# Generated by FakeRAM 2.0
VERSION 5.7 ;
BUSBITCHARS "[]" ;
PROPERTYDEFINITIONS
  MACRO width INTEGER ;
  MACRO depth INTEGER ;
  MACRO banks INTEGER ;
END PROPERTYDEFINITIONS
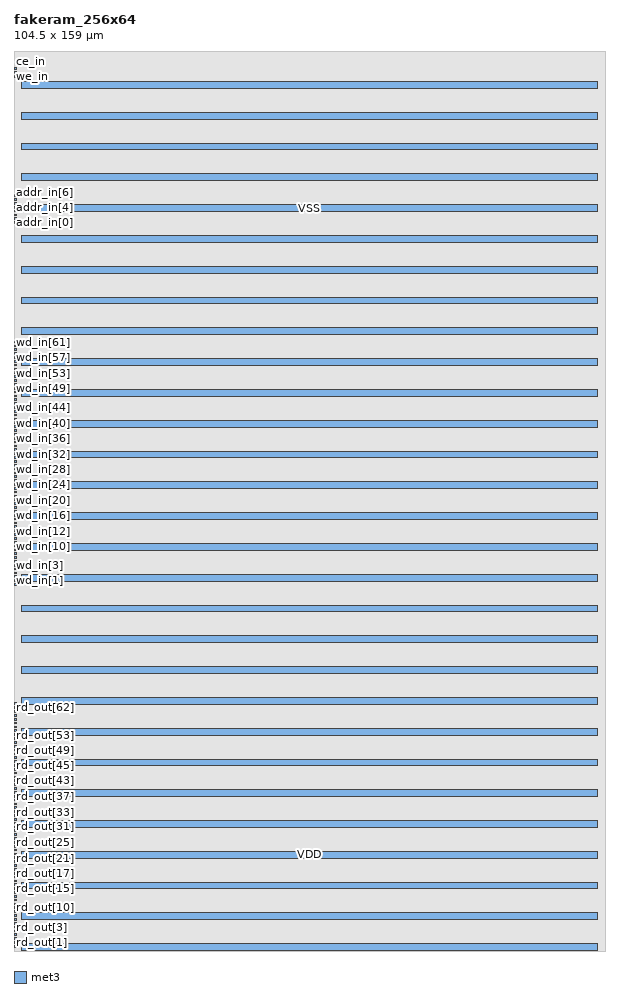
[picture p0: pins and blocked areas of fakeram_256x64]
MACRO fakeram_256x64
  PROPERTY width 64 ;
  PROPERTY depth 256 ;
  PROPERTY banks 1 ;
  FOREIGN fakeram_256x64 0 0 ;
  SYMMETRY X Y R90 ;
  SIZE 104.5000 BY 159.0000 ;
  CLASS BLOCK ;
  PIN rd_out[0]
    DIRECTION OUTPUT ;
    USE SIGNAL ;
    PORT
      LAYER met3 ;
      RECT 0.00000 0.68000 0.45000 0.98000 ;
    END
  END rd_out[0]
  PIN rd_out[1]
    DIRECTION OUTPUT ;
    USE SIGNAL ;
    PORT
      LAYER met3 ;
      RECT 0.00000 1.36000 0.45000 1.66000 ;
    END
  END rd_out[1]
  PIN rd_out[2]
    DIRECTION OUTPUT ;
    USE SIGNAL ;
    PORT
      LAYER met3 ;
      RECT 0.00000 2.04000 0.45000 2.34000 ;
    END
  END rd_out[2]
  PIN rd_out[3]
    DIRECTION OUTPUT ;
    USE SIGNAL ;
    PORT
      LAYER met3 ;
      RECT 0.00000 2.72000 0.45000 3.02000 ;
    END
  END rd_out[3]
  PIN rd_out[4]
    DIRECTION OUTPUT ;
    USE SIGNAL ;
    PORT
      LAYER met3 ;
      RECT 0.00000 3.40000 0.45000 3.70000 ;
    END
  END rd_out[4]
  PIN rd_out[5]
    DIRECTION OUTPUT ;
    USE SIGNAL ;
    PORT
      LAYER met3 ;
      RECT 0.00000 4.08000 0.45000 4.38000 ;
    END
  END rd_out[5]
  PIN rd_out[6]
    DIRECTION OUTPUT ;
    USE SIGNAL ;
    PORT
      LAYER met3 ;
      RECT 0.00000 4.76000 0.45000 5.06000 ;
    END
  END rd_out[6]
  PIN rd_out[7]
    DIRECTION OUTPUT ;
    USE SIGNAL ;
    PORT
      LAYER met3 ;
      RECT 0.00000 5.44000 0.45000 5.74000 ;
    END
  END rd_out[7]
  PIN rd_out[8]
    DIRECTION OUTPUT ;
    USE SIGNAL ;
    PORT
      LAYER met3 ;
      RECT 0.00000 6.12000 0.45000 6.42000 ;
    END
  END rd_out[8]
  PIN rd_out[9]
    DIRECTION OUTPUT ;
    USE SIGNAL ;
    PORT
      LAYER met3 ;
      RECT 0.00000 6.80000 0.45000 7.10000 ;
    END
  END rd_out[9]
  PIN rd_out[10]
    DIRECTION OUTPUT ;
    USE SIGNAL ;
    PORT
      LAYER met3 ;
      RECT 0.00000 7.48000 0.45000 7.78000 ;
    END
  END rd_out[10]
  PIN rd_out[11]
    DIRECTION OUTPUT ;
    USE SIGNAL ;
    PORT
      LAYER met3 ;
      RECT 0.00000 8.16000 0.45000 8.46000 ;
    END
  END rd_out[11]
  PIN rd_out[12]
    DIRECTION OUTPUT ;
    USE SIGNAL ;
    PORT
      LAYER met3 ;
      RECT 0.00000 8.84000 0.45000 9.14000 ;
    END
  END rd_out[12]
  PIN rd_out[13]
    DIRECTION OUTPUT ;
    USE SIGNAL ;
    PORT
      LAYER met3 ;
      RECT 0.00000 9.52000 0.45000 9.82000 ;
    END
  END rd_out[13]
  PIN rd_out[14]
    DIRECTION OUTPUT ;
    USE SIGNAL ;
    PORT
      LAYER met3 ;
      RECT 0.00000 10.20000 0.45000 10.50000 ;
    END
  END rd_out[14]
  PIN rd_out[15]
    DIRECTION OUTPUT ;
    USE SIGNAL ;
    PORT
      LAYER met3 ;
      RECT 0.00000 10.88000 0.45000 11.18000 ;
    END
  END rd_out[15]
  PIN rd_out[16]
    DIRECTION OUTPUT ;
    USE SIGNAL ;
    PORT
      LAYER met3 ;
      RECT 0.00000 11.56000 0.45000 11.86000 ;
    END
  END rd_out[16]
  PIN rd_out[17]
    DIRECTION OUTPUT ;
    USE SIGNAL ;
    PORT
      LAYER met3 ;
      RECT 0.00000 12.24000 0.45000 12.54000 ;
    END
  END rd_out[17]
  PIN rd_out[18]
    DIRECTION OUTPUT ;
    USE SIGNAL ;
    PORT
      LAYER met3 ;
      RECT 0.00000 12.92000 0.45000 13.22000 ;
    END
  END rd_out[18]
  PIN rd_out[19]
    DIRECTION OUTPUT ;
    USE SIGNAL ;
    PORT
      LAYER met3 ;
      RECT 0.00000 13.60000 0.45000 13.90000 ;
    END
  END rd_out[19]
  PIN rd_out[20]
    DIRECTION OUTPUT ;
    USE SIGNAL ;
    PORT
      LAYER met3 ;
      RECT 0.00000 14.28000 0.45000 14.58000 ;
    END
  END rd_out[20]
  PIN rd_out[21]
    DIRECTION OUTPUT ;
    USE SIGNAL ;
    PORT
      LAYER met3 ;
      RECT 0.00000 14.96000 0.45000 15.26000 ;
    END
  END rd_out[21]
  PIN rd_out[22]
    DIRECTION OUTPUT ;
    USE SIGNAL ;
    PORT
      LAYER met3 ;
      RECT 0.00000 15.64000 0.45000 15.94000 ;
    END
  END rd_out[22]
  PIN rd_out[23]
    DIRECTION OUTPUT ;
    USE SIGNAL ;
    PORT
      LAYER met3 ;
      RECT 0.00000 16.32000 0.45000 16.62000 ;
    END
  END rd_out[23]
  PIN rd_out[24]
    DIRECTION OUTPUT ;
    USE SIGNAL ;
    PORT
      LAYER met3 ;
      RECT 0.00000 17.00000 0.45000 17.30000 ;
    END
  END rd_out[24]
  PIN rd_out[25]
    DIRECTION OUTPUT ;
    USE SIGNAL ;
    PORT
      LAYER met3 ;
      RECT 0.00000 17.68000 0.45000 17.98000 ;
    END
  END rd_out[25]
  PIN rd_out[26]
    DIRECTION OUTPUT ;
    USE SIGNAL ;
    PORT
      LAYER met3 ;
      RECT 0.00000 18.36000 0.45000 18.66000 ;
    END
  END rd_out[26]
  PIN rd_out[27]
    DIRECTION OUTPUT ;
    USE SIGNAL ;
    PORT
      LAYER met3 ;
      RECT 0.00000 19.04000 0.45000 19.34000 ;
    END
  END rd_out[27]
  PIN rd_out[28]
    DIRECTION OUTPUT ;
    USE SIGNAL ;
    PORT
      LAYER met3 ;
      RECT 0.00000 19.72000 0.45000 20.02000 ;
    END
  END rd_out[28]
  PIN rd_out[29]
    DIRECTION OUTPUT ;
    USE SIGNAL ;
    PORT
      LAYER met3 ;
      RECT 0.00000 20.40000 0.45000 20.70000 ;
    END
  END rd_out[29]
  PIN rd_out[30]
    DIRECTION OUTPUT ;
    USE SIGNAL ;
    PORT
      LAYER met3 ;
      RECT 0.00000 21.08000 0.45000 21.38000 ;
    END
  END rd_out[30]
  PIN rd_out[31]
    DIRECTION OUTPUT ;
    USE SIGNAL ;
    PORT
      LAYER met3 ;
      RECT 0.00000 21.76000 0.45000 22.06000 ;
    END
  END rd_out[31]
  PIN rd_out[32]
    DIRECTION OUTPUT ;
    USE SIGNAL ;
    PORT
      LAYER met3 ;
      RECT 0.00000 22.44000 0.45000 22.74000 ;
    END
  END rd_out[32]
  PIN rd_out[33]
    DIRECTION OUTPUT ;
    USE SIGNAL ;
    PORT
      LAYER met3 ;
      RECT 0.00000 23.12000 0.45000 23.42000 ;
    END
  END rd_out[33]
  PIN rd_out[34]
    DIRECTION OUTPUT ;
    USE SIGNAL ;
    PORT
      LAYER met3 ;
      RECT 0.00000 23.80000 0.45000 24.10000 ;
    END
  END rd_out[34]
  PIN rd_out[35]
    DIRECTION OUTPUT ;
    USE SIGNAL ;
    PORT
      LAYER met3 ;
      RECT 0.00000 24.48000 0.45000 24.78000 ;
    END
  END rd_out[35]
  PIN rd_out[36]
    DIRECTION OUTPUT ;
    USE SIGNAL ;
    PORT
      LAYER met3 ;
      RECT 0.00000 25.16000 0.45000 25.46000 ;
    END
  END rd_out[36]
  PIN rd_out[37]
    DIRECTION OUTPUT ;
    USE SIGNAL ;
    PORT
      LAYER met3 ;
      RECT 0.00000 25.84000 0.45000 26.14000 ;
    END
  END rd_out[37]
  PIN rd_out[38]
    DIRECTION OUTPUT ;
    USE SIGNAL ;
    PORT
      LAYER met3 ;
      RECT 0.00000 26.52000 0.45000 26.82000 ;
    END
  END rd_out[38]
  PIN rd_out[39]
    DIRECTION OUTPUT ;
    USE SIGNAL ;
    PORT
      LAYER met3 ;
      RECT 0.00000 27.20000 0.45000 27.50000 ;
    END
  END rd_out[39]
  PIN rd_out[40]
    DIRECTION OUTPUT ;
    USE SIGNAL ;
    PORT
      LAYER met3 ;
      RECT 0.00000 27.88000 0.45000 28.18000 ;
    END
  END rd_out[40]
  PIN rd_out[41]
    DIRECTION OUTPUT ;
    USE SIGNAL ;
    PORT
      LAYER met3 ;
      RECT 0.00000 28.56000 0.45000 28.86000 ;
    END
  END rd_out[41]
  PIN rd_out[42]
    DIRECTION OUTPUT ;
    USE SIGNAL ;
    PORT
      LAYER met3 ;
      RECT 0.00000 29.24000 0.45000 29.54000 ;
    END
  END rd_out[42]
  PIN rd_out[43]
    DIRECTION OUTPUT ;
    USE SIGNAL ;
    PORT
      LAYER met3 ;
      RECT 0.00000 29.92000 0.45000 30.22000 ;
    END
  END rd_out[43]
  PIN rd_out[44]
    DIRECTION OUTPUT ;
    USE SIGNAL ;
    PORT
      LAYER met3 ;
      RECT 0.00000 30.60000 0.45000 30.90000 ;
    END
  END rd_out[44]
  PIN rd_out[45]
    DIRECTION OUTPUT ;
    USE SIGNAL ;
    PORT
      LAYER met3 ;
      RECT 0.00000 31.28000 0.45000 31.58000 ;
    END
  END rd_out[45]
  PIN rd_out[46]
    DIRECTION OUTPUT ;
    USE SIGNAL ;
    PORT
      LAYER met3 ;
      RECT 0.00000 31.96000 0.45000 32.26000 ;
    END
  END rd_out[46]
  PIN rd_out[47]
    DIRECTION OUTPUT ;
    USE SIGNAL ;
    PORT
      LAYER met3 ;
      RECT 0.00000 32.64000 0.45000 32.94000 ;
    END
  END rd_out[47]
  PIN rd_out[48]
    DIRECTION OUTPUT ;
    USE SIGNAL ;
    PORT
      LAYER met3 ;
      RECT 0.00000 33.32000 0.45000 33.62000 ;
    END
  END rd_out[48]
  PIN rd_out[49]
    DIRECTION OUTPUT ;
    USE SIGNAL ;
    PORT
      LAYER met3 ;
      RECT 0.00000 34.00000 0.45000 34.30000 ;
    END
  END rd_out[49]
  PIN rd_out[50]
    DIRECTION OUTPUT ;
    USE SIGNAL ;
    PORT
      LAYER met3 ;
      RECT 0.00000 34.68000 0.45000 34.98000 ;
    END
  END rd_out[50]
  PIN rd_out[51]
    DIRECTION OUTPUT ;
    USE SIGNAL ;
    PORT
      LAYER met3 ;
      RECT 0.00000 35.36000 0.45000 35.66000 ;
    END
  END rd_out[51]
  PIN rd_out[52]
    DIRECTION OUTPUT ;
    USE SIGNAL ;
    PORT
      LAYER met3 ;
      RECT 0.00000 36.04000 0.45000 36.34000 ;
    END
  END rd_out[52]
  PIN rd_out[53]
    DIRECTION OUTPUT ;
    USE SIGNAL ;
    PORT
      LAYER met3 ;
      RECT 0.00000 36.72000 0.45000 37.02000 ;
    END
  END rd_out[53]
  PIN rd_out[54]
    DIRECTION OUTPUT ;
    USE SIGNAL ;
    PORT
      LAYER met3 ;
      RECT 0.00000 37.40000 0.45000 37.70000 ;
    END
  END rd_out[54]
  PIN rd_out[55]
    DIRECTION OUTPUT ;
    USE SIGNAL ;
    PORT
      LAYER met3 ;
      RECT 0.00000 38.08000 0.45000 38.38000 ;
    END
  END rd_out[55]
  PIN rd_out[56]
    DIRECTION OUTPUT ;
    USE SIGNAL ;
    PORT
      LAYER met3 ;
      RECT 0.00000 38.76000 0.45000 39.06000 ;
    END
  END rd_out[56]
  PIN rd_out[57]
    DIRECTION OUTPUT ;
    USE SIGNAL ;
    PORT
      LAYER met3 ;
      RECT 0.00000 39.44000 0.45000 39.74000 ;
    END
  END rd_out[57]
  PIN rd_out[58]
    DIRECTION OUTPUT ;
    USE SIGNAL ;
    PORT
      LAYER met3 ;
      RECT 0.00000 40.12000 0.45000 40.42000 ;
    END
  END rd_out[58]
  PIN rd_out[59]
    DIRECTION OUTPUT ;
    USE SIGNAL ;
    PORT
      LAYER met3 ;
      RECT 0.00000 40.80000 0.45000 41.10000 ;
    END
  END rd_out[59]
  PIN rd_out[60]
    DIRECTION OUTPUT ;
    USE SIGNAL ;
    PORT
      LAYER met3 ;
      RECT 0.00000 41.48000 0.45000 41.78000 ;
    END
  END rd_out[60]
  PIN rd_out[61]
    DIRECTION OUTPUT ;
    USE SIGNAL ;
    PORT
      LAYER met3 ;
      RECT 0.00000 42.16000 0.45000 42.46000 ;
    END
  END rd_out[61]
  PIN rd_out[62]
    DIRECTION OUTPUT ;
    USE SIGNAL ;
    PORT
      LAYER met3 ;
      RECT 0.00000 42.84000 0.45000 43.14000 ;
    END
  END rd_out[62]
  PIN rd_out[63]
    DIRECTION OUTPUT ;
    USE SIGNAL ;
    PORT
      LAYER met3 ;
      RECT 0.00000 43.52000 0.45000 43.82000 ;
    END
  END rd_out[63]
  PIN wd_in[0]
    DIRECTION INPUT ;
    USE SIGNAL ;
    PORT
      LAYER met3 ;
      RECT 0.00000 64.60000 0.45000 64.90000 ;
    END
  END wd_in[0]
  PIN wd_in[1]
    DIRECTION INPUT ;
    USE SIGNAL ;
    PORT
      LAYER met3 ;
      RECT 0.00000 65.28000 0.45000 65.58000 ;
    END
  END wd_in[1]
  PIN wd_in[2]
    DIRECTION INPUT ;
    USE SIGNAL ;
    PORT
      LAYER met3 ;
      RECT 0.00000 65.96000 0.45000 66.26000 ;
    END
  END wd_in[2]
  PIN wd_in[3]
    DIRECTION INPUT ;
    USE SIGNAL ;
    PORT
      LAYER met3 ;
      RECT 0.00000 66.64000 0.45000 66.94000 ;
    END
  END wd_in[3]
  PIN wd_in[4]
    DIRECTION INPUT ;
    USE SIGNAL ;
    PORT
      LAYER met3 ;
      RECT 0.00000 67.32000 0.45000 67.62000 ;
    END
  END wd_in[4]
  PIN wd_in[5]
    DIRECTION INPUT ;
    USE SIGNAL ;
    PORT
      LAYER met3 ;
      RECT 0.00000 68.00000 0.45000 68.30000 ;
    END
  END wd_in[5]
  PIN wd_in[6]
    DIRECTION INPUT ;
    USE SIGNAL ;
    PORT
      LAYER met3 ;
      RECT 0.00000 68.68000 0.45000 68.98000 ;
    END
  END wd_in[6]
  PIN wd_in[7]
    DIRECTION INPUT ;
    USE SIGNAL ;
    PORT
      LAYER met3 ;
      RECT 0.00000 69.36000 0.45000 69.66000 ;
    END
  END wd_in[7]
  PIN wd_in[8]
    DIRECTION INPUT ;
    USE SIGNAL ;
    PORT
      LAYER met3 ;
      RECT 0.00000 70.04000 0.45000 70.34000 ;
    END
  END wd_in[8]
  PIN wd_in[9]
    DIRECTION INPUT ;
    USE SIGNAL ;
    PORT
      LAYER met3 ;
      RECT 0.00000 70.72000 0.45000 71.02000 ;
    END
  END wd_in[9]
  PIN wd_in[10]
    DIRECTION INPUT ;
    USE SIGNAL ;
    PORT
      LAYER met3 ;
      RECT 0.00000 71.40000 0.45000 71.70000 ;
    END
  END wd_in[10]
  PIN wd_in[11]
    DIRECTION INPUT ;
    USE SIGNAL ;
    PORT
      LAYER met3 ;
      RECT 0.00000 72.08000 0.45000 72.38000 ;
    END
  END wd_in[11]
  PIN wd_in[12]
    DIRECTION INPUT ;
    USE SIGNAL ;
    PORT
      LAYER met3 ;
      RECT 0.00000 72.76000 0.45000 73.06000 ;
    END
  END wd_in[12]
  PIN wd_in[13]
    DIRECTION INPUT ;
    USE SIGNAL ;
    PORT
      LAYER met3 ;
      RECT 0.00000 73.44000 0.45000 73.74000 ;
    END
  END wd_in[13]
  PIN wd_in[14]
    DIRECTION INPUT ;
    USE SIGNAL ;
    PORT
      LAYER met3 ;
      RECT 0.00000 74.12000 0.45000 74.42000 ;
    END
  END wd_in[14]
  PIN wd_in[15]
    DIRECTION INPUT ;
    USE SIGNAL ;
    PORT
      LAYER met3 ;
      RECT 0.00000 74.80000 0.45000 75.10000 ;
    END
  END wd_in[15]
  PIN wd_in[16]
    DIRECTION INPUT ;
    USE SIGNAL ;
    PORT
      LAYER met3 ;
      RECT 0.00000 75.48000 0.45000 75.78000 ;
    END
  END wd_in[16]
  PIN wd_in[17]
    DIRECTION INPUT ;
    USE SIGNAL ;
    PORT
      LAYER met3 ;
      RECT 0.00000 76.16000 0.45000 76.46000 ;
    END
  END wd_in[17]
  PIN wd_in[18]
    DIRECTION INPUT ;
    USE SIGNAL ;
    PORT
      LAYER met3 ;
      RECT 0.00000 76.84000 0.45000 77.14000 ;
    END
  END wd_in[18]
  PIN wd_in[19]
    DIRECTION INPUT ;
    USE SIGNAL ;
    PORT
      LAYER met3 ;
      RECT 0.00000 77.52000 0.45000 77.82000 ;
    END
  END wd_in[19]
  PIN wd_in[20]
    DIRECTION INPUT ;
    USE SIGNAL ;
    PORT
      LAYER met3 ;
      RECT 0.00000 78.20000 0.45000 78.50000 ;
    END
  END wd_in[20]
  PIN wd_in[21]
    DIRECTION INPUT ;
    USE SIGNAL ;
    PORT
      LAYER met3 ;
      RECT 0.00000 78.88000 0.45000 79.18000 ;
    END
  END wd_in[21]
  PIN wd_in[22]
    DIRECTION INPUT ;
    USE SIGNAL ;
    PORT
      LAYER met3 ;
      RECT 0.00000 79.56000 0.45000 79.86000 ;
    END
  END wd_in[22]
  PIN wd_in[23]
    DIRECTION INPUT ;
    USE SIGNAL ;
    PORT
      LAYER met3 ;
      RECT 0.00000 80.24000 0.45000 80.54000 ;
    END
  END wd_in[23]
  PIN wd_in[24]
    DIRECTION INPUT ;
    USE SIGNAL ;
    PORT
      LAYER met3 ;
      RECT 0.00000 80.92000 0.45000 81.22000 ;
    END
  END wd_in[24]
  PIN wd_in[25]
    DIRECTION INPUT ;
    USE SIGNAL ;
    PORT
      LAYER met3 ;
      RECT 0.00000 81.60000 0.45000 81.90000 ;
    END
  END wd_in[25]
  PIN wd_in[26]
    DIRECTION INPUT ;
    USE SIGNAL ;
    PORT
      LAYER met3 ;
      RECT 0.00000 82.28000 0.45000 82.58000 ;
    END
  END wd_in[26]
  PIN wd_in[27]
    DIRECTION INPUT ;
    USE SIGNAL ;
    PORT
      LAYER met3 ;
      RECT 0.00000 82.96000 0.45000 83.26000 ;
    END
  END wd_in[27]
  PIN wd_in[28]
    DIRECTION INPUT ;
    USE SIGNAL ;
    PORT
      LAYER met3 ;
      RECT 0.00000 83.64000 0.45000 83.94000 ;
    END
  END wd_in[28]
  PIN wd_in[29]
    DIRECTION INPUT ;
    USE SIGNAL ;
    PORT
      LAYER met3 ;
      RECT 0.00000 84.32000 0.45000 84.62000 ;
    END
  END wd_in[29]
  PIN wd_in[30]
    DIRECTION INPUT ;
    USE SIGNAL ;
    PORT
      LAYER met3 ;
      RECT 0.00000 85.00000 0.45000 85.30000 ;
    END
  END wd_in[30]
  PIN wd_in[31]
    DIRECTION INPUT ;
    USE SIGNAL ;
    PORT
      LAYER met3 ;
      RECT 0.00000 85.68000 0.45000 85.98000 ;
    END
  END wd_in[31]
  PIN wd_in[32]
    DIRECTION INPUT ;
    USE SIGNAL ;
    PORT
      LAYER met3 ;
      RECT 0.00000 86.36000 0.45000 86.66000 ;
    END
  END wd_in[32]
  PIN wd_in[33]
    DIRECTION INPUT ;
    USE SIGNAL ;
    PORT
      LAYER met3 ;
      RECT 0.00000 87.04000 0.45000 87.34000 ;
    END
  END wd_in[33]
  PIN wd_in[34]
    DIRECTION INPUT ;
    USE SIGNAL ;
    PORT
      LAYER met3 ;
      RECT 0.00000 87.72000 0.45000 88.02000 ;
    END
  END wd_in[34]
  PIN wd_in[35]
    DIRECTION INPUT ;
    USE SIGNAL ;
    PORT
      LAYER met3 ;
      RECT 0.00000 88.40000 0.45000 88.70000 ;
    END
  END wd_in[35]
  PIN wd_in[36]
    DIRECTION INPUT ;
    USE SIGNAL ;
    PORT
      LAYER met3 ;
      RECT 0.00000 89.08000 0.45000 89.38000 ;
    END
  END wd_in[36]
  PIN wd_in[37]
    DIRECTION INPUT ;
    USE SIGNAL ;
    PORT
      LAYER met3 ;
      RECT 0.00000 89.76000 0.45000 90.06000 ;
    END
  END wd_in[37]
  PIN wd_in[38]
    DIRECTION INPUT ;
    USE SIGNAL ;
    PORT
      LAYER met3 ;
      RECT 0.00000 90.44000 0.45000 90.74000 ;
    END
  END wd_in[38]
  PIN wd_in[39]
    DIRECTION INPUT ;
    USE SIGNAL ;
    PORT
      LAYER met3 ;
      RECT 0.00000 91.12000 0.45000 91.42000 ;
    END
  END wd_in[39]
  PIN wd_in[40]
    DIRECTION INPUT ;
    USE SIGNAL ;
    PORT
      LAYER met3 ;
      RECT 0.00000 91.80000 0.45000 92.10000 ;
    END
  END wd_in[40]
  PIN wd_in[41]
    DIRECTION INPUT ;
    USE SIGNAL ;
    PORT
      LAYER met3 ;
      RECT 0.00000 92.48000 0.45000 92.78000 ;
    END
  END wd_in[41]
  PIN wd_in[42]
    DIRECTION INPUT ;
    USE SIGNAL ;
    PORT
      LAYER met3 ;
      RECT 0.00000 93.16000 0.45000 93.46000 ;
    END
  END wd_in[42]
  PIN wd_in[43]
    DIRECTION INPUT ;
    USE SIGNAL ;
    PORT
      LAYER met3 ;
      RECT 0.00000 93.84000 0.45000 94.14000 ;
    END
  END wd_in[43]
  PIN wd_in[44]
    DIRECTION INPUT ;
    USE SIGNAL ;
    PORT
      LAYER met3 ;
      RECT 0.00000 94.52000 0.45000 94.82000 ;
    END
  END wd_in[44]
  PIN wd_in[45]
    DIRECTION INPUT ;
    USE SIGNAL ;
    PORT
      LAYER met3 ;
      RECT 0.00000 95.20000 0.45000 95.50000 ;
    END
  END wd_in[45]
  PIN wd_in[46]
    DIRECTION INPUT ;
    USE SIGNAL ;
    PORT
      LAYER met3 ;
      RECT 0.00000 95.88000 0.45000 96.18000 ;
    END
  END wd_in[46]
  PIN wd_in[47]
    DIRECTION INPUT ;
    USE SIGNAL ;
    PORT
      LAYER met3 ;
      RECT 0.00000 96.56000 0.45000 96.86000 ;
    END
  END wd_in[47]
  PIN wd_in[48]
    DIRECTION INPUT ;
    USE SIGNAL ;
    PORT
      LAYER met3 ;
      RECT 0.00000 97.24000 0.45000 97.54000 ;
    END
  END wd_in[48]
  PIN wd_in[49]
    DIRECTION INPUT ;
    USE SIGNAL ;
    PORT
      LAYER met3 ;
      RECT 0.00000 97.92000 0.45000 98.22000 ;
    END
  END wd_in[49]
  PIN wd_in[50]
    DIRECTION INPUT ;
    USE SIGNAL ;
    PORT
      LAYER met3 ;
      RECT 0.00000 98.60000 0.45000 98.90000 ;
    END
  END wd_in[50]
  PIN wd_in[51]
    DIRECTION INPUT ;
    USE SIGNAL ;
    PORT
      LAYER met3 ;
      RECT 0.00000 99.28000 0.45000 99.58000 ;
    END
  END wd_in[51]
  PIN wd_in[52]
    DIRECTION INPUT ;
    USE SIGNAL ;
    PORT
      LAYER met3 ;
      RECT 0.00000 99.96000 0.45000 100.26000 ;
    END
  END wd_in[52]
  PIN wd_in[53]
    DIRECTION INPUT ;
    USE SIGNAL ;
    PORT
      LAYER met3 ;
      RECT 0.00000 100.64000 0.45000 100.94000 ;
    END
  END wd_in[53]
  PIN wd_in[54]
    DIRECTION INPUT ;
    USE SIGNAL ;
    PORT
      LAYER met3 ;
      RECT 0.00000 101.32000 0.45000 101.62000 ;
    END
  END wd_in[54]
  PIN wd_in[55]
    DIRECTION INPUT ;
    USE SIGNAL ;
    PORT
      LAYER met3 ;
      RECT 0.00000 102.00000 0.45000 102.30000 ;
    END
  END wd_in[55]
  PIN wd_in[56]
    DIRECTION INPUT ;
    USE SIGNAL ;
    PORT
      LAYER met3 ;
      RECT 0.00000 102.68000 0.45000 102.98000 ;
    END
  END wd_in[56]
  PIN wd_in[57]
    DIRECTION INPUT ;
    USE SIGNAL ;
    PORT
      LAYER met3 ;
      RECT 0.00000 103.36000 0.45000 103.66000 ;
    END
  END wd_in[57]
  PIN wd_in[58]
    DIRECTION INPUT ;
    USE SIGNAL ;
    PORT
      LAYER met3 ;
      RECT 0.00000 104.04000 0.45000 104.34000 ;
    END
  END wd_in[58]
  PIN wd_in[59]
    DIRECTION INPUT ;
    USE SIGNAL ;
    PORT
      LAYER met3 ;
      RECT 0.00000 104.72000 0.45000 105.02000 ;
    END
  END wd_in[59]
  PIN wd_in[60]
    DIRECTION INPUT ;
    USE SIGNAL ;
    PORT
      LAYER met3 ;
      RECT 0.00000 105.40000 0.45000 105.70000 ;
    END
  END wd_in[60]
  PIN wd_in[61]
    DIRECTION INPUT ;
    USE SIGNAL ;
    PORT
      LAYER met3 ;
      RECT 0.00000 106.08000 0.45000 106.38000 ;
    END
  END wd_in[61]
  PIN wd_in[62]
    DIRECTION INPUT ;
    USE SIGNAL ;
    PORT
      LAYER met3 ;
      RECT 0.00000 106.76000 0.45000 107.06000 ;
    END
  END wd_in[62]
  PIN wd_in[63]
    DIRECTION INPUT ;
    USE SIGNAL ;
    PORT
      LAYER met3 ;
      RECT 0.00000 107.44000 0.45000 107.74000 ;
    END
  END wd_in[63]
  PIN addr_in[0]
    DIRECTION INPUT ;
    USE SIGNAL ;
    PORT
      LAYER met3 ;
      RECT 0.00000 128.52000 0.45000 128.82000 ;
    END
  END addr_in[0]
  PIN addr_in[1]
    DIRECTION INPUT ;
    USE SIGNAL ;
    PORT
      LAYER met3 ;
      RECT 0.00000 129.20000 0.45000 129.50000 ;
    END
  END addr_in[1]
  PIN addr_in[2]
    DIRECTION INPUT ;
    USE SIGNAL ;
    PORT
      LAYER met3 ;
      RECT 0.00000 129.88000 0.45000 130.18000 ;
    END
  END addr_in[2]
  PIN addr_in[3]
    DIRECTION INPUT ;
    USE SIGNAL ;
    PORT
      LAYER met3 ;
      RECT 0.00000 130.56000 0.45000 130.86000 ;
    END
  END addr_in[3]
  PIN addr_in[4]
    DIRECTION INPUT ;
    USE SIGNAL ;
    PORT
      LAYER met3 ;
      RECT 0.00000 131.24000 0.45000 131.54000 ;
    END
  END addr_in[4]
  PIN addr_in[5]
    DIRECTION INPUT ;
    USE SIGNAL ;
    PORT
      LAYER met3 ;
      RECT 0.00000 131.92000 0.45000 132.22000 ;
    END
  END addr_in[5]
  PIN addr_in[6]
    DIRECTION INPUT ;
    USE SIGNAL ;
    PORT
      LAYER met3 ;
      RECT 0.00000 132.60000 0.45000 132.90000 ;
    END
  END addr_in[6]
  PIN addr_in[7]
    DIRECTION INPUT ;
    USE SIGNAL ;
    PORT
      LAYER met3 ;
      RECT 0.00000 133.28000 0.45000 133.58000 ;
    END
  END addr_in[7]
  PIN we_in
    DIRECTION INPUT ;
    USE SIGNAL ;
    PORT
      LAYER met3 ;
      RECT 0.00000 154.36000 0.45000 154.66000 ;
    END
  END we_in
  PIN clk
    DIRECTION INPUT ;
    USE SIGNAL ;
    PORT
      LAYER met3 ;
      RECT 0.00000 155.04000 0.45000 155.34000 ;
    END
  END clk
  PIN ce_in
    DIRECTION INPUT ;
    USE SIGNAL ;
    PORT
      LAYER met3 ;
      RECT 0.00000 155.72000 0.45000 156.02000 ;
    END
  END ce_in
  PIN VDD
    DIRECTION INOUT ;
    USE POWER ;
    PORT
      LAYER met3 ;
      RECT 1.36000 5.52000 103.14000 6.72000 ;
      RECT 1.36000 16.40000 103.14000 17.60000 ;
      RECT 1.36000 27.28000 103.14000 28.48000 ;
      RECT 1.36000 38.16000 103.14000 39.36000 ;
      RECT 1.36000 49.04000 103.14000 50.24000 ;
      RECT 1.36000 59.92000 103.14000 61.12000 ;
      RECT 1.36000 70.80000 103.14000 72.00000 ;
      RECT 1.36000 81.68000 103.14000 82.88000 ;
      RECT 1.36000 92.56000 103.14000 93.76000 ;
      RECT 1.36000 103.44000 103.14000 104.64000 ;
      RECT 1.36000 114.32000 103.14000 115.52000 ;
      RECT 1.36000 125.20000 103.14000 126.40000 ;
      RECT 1.36000 136.08000 103.14000 137.28000 ;
      RECT 1.36000 146.96000 103.14000 148.16000 ;
    END
  END VDD
  PIN VSS
    DIRECTION INOUT ;
    USE GROUND ;
    PORT
      LAYER met3 ;
      RECT 1.36000 0.08000 103.14000 1.28000 ;
      RECT 1.36000 10.96000 103.14000 12.16000 ;
      RECT 1.36000 21.84000 103.14000 23.04000 ;
      RECT 1.36000 32.72000 103.14000 33.92000 ;
      RECT 1.36000 43.60000 103.14000 44.80000 ;
      RECT 1.36000 54.48000 103.14000 55.68000 ;
      RECT 1.36000 65.36000 103.14000 66.56000 ;
      RECT 1.36000 76.24000 103.14000 77.44000 ;
      RECT 1.36000 87.12000 103.14000 88.32000 ;
      RECT 1.36000 98.00000 103.14000 99.20000 ;
      RECT 1.36000 108.88000 103.14000 110.08000 ;
      RECT 1.36000 119.76000 103.14000 120.96000 ;
      RECT 1.36000 130.64000 103.14000 131.84000 ;
      RECT 1.36000 141.52000 103.14000 142.72000 ;
      RECT 1.36000 152.40000 103.14000 153.60000 ;
    END
  END VSS
  OBS
    LAYER met1 ;
    RECT 0 0 104.50000 159.00000 ;
    LAYER met2 ;
    RECT 0 0 104.50000 159.00000 ;
    LAYER met3 ;
    RECT 0 0 104.50000 159.00000 ;
  END
END fakeram_256x64

END LIBRARY
